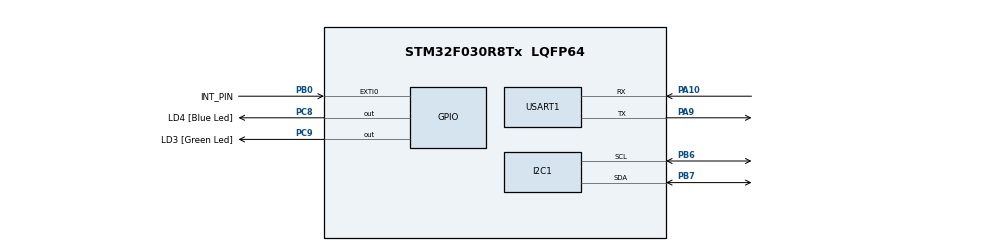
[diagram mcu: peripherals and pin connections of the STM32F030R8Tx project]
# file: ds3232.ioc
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Mcu.Family=STM32F0
PA10.Mode=Asynchronous
PC9.GPIO_Label=LD3 [Green Led]
PA14.GPIO_Label=SWCLK
PC8.Signal=GPIO_Output
PB0.GPIO_Label=INT_PIN
RCC.SYSCLKSource=RCC_SYSCLKSOURCE_PLLCLK
ProjectManager.StackSize=0x400
PC8.GPIO_Label=LD4 [Blue Led]
USART1.VirtualMode-Asynchronous=VM_ASYNC
PA13.Signal=SYS_SWDIO
PA9.Mode=Asynchronous
ProjectManager.TargetToolchain=STM32CubeIDE
RCC.HCLKFreq_Value=48000000
PA9.Signal=USART1_TX
PB6.Signal=I2C1_SCL
PB6.Mode=I2C
RCC.AHBFreq_Value=48000000
board=STM32F0308-DISCO
RCC.PLLMUL=RCC_PLL_MUL12
PB0.GPIO_ModeDefaultEXTI=GPIO_MODE_IT_FALLING
PA14.Mode=Serial_Wire
PB7.Signal=I2C1_SDA
PA13.Mode=Serial_Wire
Mcu.Name=STM32F030R8Tx
PA13.GPIO_Label=SWDIO
RCC.SYSCLKFreq_VALUE=48000000
Mcu.Package=LQFP64
PB7.Mode=I2C
PA10.Signal=USART1_RX
PA14.Signal=SYS_SWCLK
ProjectManager.HeapSize=0x200
RCC.APB1TimFreq_Value=48000000
PC9.Signal=GPIO_Output
RCC.APB1Freq_Value=48000000
PB0.Signal=GPXTI0
PB0.GPIO_PuPd=GPIO_PULLUP
NVIC.EXTI0_1_IRQn=true\:0\:0\:false\:false\:true\:true\:true

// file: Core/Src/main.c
/* USER CODE BEGIN Header */
/**
 ******************************************************************************
 * @file           : main.c
 * @brief          : Main program body
 ******************************************************************************
 * @attention
 *
 * <h2><center>&copy; Copyright (c) 2020 STMicroelectronics.
 * All rights reserved.</center></h2>
 *
 * This software component is licensed by ST under BSD 3-Clause license,
 * the "License"; You may not use this file except in compliance with the
 * License. You may obtain a copy of the License at:
 *                        opensource.org/licenses/BSD-3-Clause
 *
 ******************************************************************************
 */
/* USER CODE END Header */

#include "main.h"

/* USER CODE BEGIN Includes */
#include <stdio.h>
#include "ds3231_for_stm32_hal.h"
/* USER CODE END Includes */

I2C_HandleTypeDef hi2c1;

UART_HandleTypeDef huart1;

void SystemClock_Config(void);
static void MX_GPIO_Init(void);
static void MX_USART1_UART_Init(void);
static void MX_I2C1_Init(void);

/* USER CODE BEGIN 0 */
void printr(uint8_t reg) {
	printf("Reg 0x%02x = ", reg);
	uint8_t val;
	HAL_I2C_Master_Transmit(_ds3231_ui2c, DS3231_I2C_ADDR << 1, &reg, 1,
			DS3231_TIMEOUT);
	HAL_StatusTypeDef s = HAL_I2C_Master_Receive(_ds3231_ui2c,
			DS3231_I2C_ADDR << 1, &val, 1, DS3231_TIMEOUT);
	for (uint8_t i = 0; i < 8; i++) {
		printf("%d", (val >> (7 - i)) & 1);
	}
	printf(" With status %d", s);
	printf("\n");
}
/* USER CODE END 0 */

int main(void) {
	__disable_irq();

	/* MCU Configuration--------------------------------------------------------*/

	/* Reset of all peripherals, Initializes the Flash interface and the Systick. */
	HAL_Init();

	/* Configure the system clock */
	SystemClock_Config();

	/* Initialize all configured peripherals */
	MX_GPIO_Init();
	MX_USART1_UART_Init();
	MX_I2C1_Init();
	/* USER CODE BEGIN 2 */
	//DS3231 init function. Pass I2C handle.
	DS3231_Init(&hi2c1);
	//Disable interrupts while we set interrupt configs.
	__disable_irq();
	//Set interrupt mode to square wave mode, enable square wave interrupt at pin 3.
	DS3231_SetInterruptMode(DS3231_SQUARE_WAVE_INTERRUPT);
	//Set interrupting frequency to 1 Hz.
	DS3231_SetRateSelect(DS3231_1HZ);
	//Set time.
	DS3231_SetFullTime(23, 59, 50);
	//Set date.
	DS3231_SetFullDate(10, 11, 2, 2020);
	//Print all register values, for demonstration purpose
  	for(uint8_t i = 0x00; i < 0x13; i++)
    		printr(i);
	//Enable interrupts after finishing.
	__enable_irq();

	//Should show 5 interrupts, once every second.
	HAL_Delay(5000);

	//Set to alarm interrupt mode.
	DS3231_SetInterruptMode(DS3231_ALARM_INTERRUPT);
	DS3231_ClearAlarm1Flag();

	//Test alarm 1
	DS3231_EnableAlarm1(DS3231_ENABLED);
	DS3231_SetAlarm1Mode(DS3231_A1_MATCH_S_M_H_DATE);
	DS3231_SetAlarm1Second(3);
	DS3231_SetAlarm1Minute(0);
	DS3231_SetAlarm1Hour(0);
	DS3231_SetAlarm1Date(11);

	//Test alarm 2
	DS3231_ClearAlarm2Flag();
	DS3231_EnableAlarm2(DS3231_ENABLED);
	DS3231_SetAlarm2Mode(DS3231_A2_MATCH_M_H_DAY);
	DS3231_SetAlarm2Minute(0);
	DS3231_SetAlarm2Hour(0);
	DS3231_SetAlarm2Day(3);

	//Check if alarm behavior is correct
	__enable_irq();
	HAL_Delay(5000);
	DS3231_SetFullTime(1, 59, 59);
	DS3231_SetDate(11);
	DS3231_SetDayOfWeek(3);
	HAL_Delay(5000);
	DS3231_SetFullTime(23, 59, 59);
	DS3231_SetDate(10);
	DS3231_SetDayOfWeek(2);
	HAL_Delay(5000);
	DS3231_SetFullTime(23, 59, 59);
	DS3231_SetDate(11);
	DS3231_SetDayOfWeek(3);
	HAL_Delay(5000);

	/* USER CODE END 2 */

	/* Infinite loop */
	while (1) {

	}
}

void SystemClock_Config(void) {
	RCC_OscInitTypeDef RCC_OscInitStruct = { 0 };
	RCC_ClkInitTypeDef RCC_ClkInitStruct = { 0 };

	/** Configure the main internal regulator output voltage
	 */
	__HAL_RCC_PWR_CLK_ENABLE();
	__HAL_PWR_VOLTAGESCALING_CONFIG(PWR_REGULATOR_VOLTAGE_SCALE2);
	/** Initializes the CPU, AHB and APB busses clocks
	 */
	RCC_OscInitStruct.OscillatorType = RCC_OSCILLATORTYPE_HSE;
	RCC_OscInitStruct.HSEState = RCC_HSE_ON;
	RCC_OscInitStruct.PLL.PLLState = RCC_PLL_NONE;
	if (HAL_RCC_OscConfig(&RCC_OscInitStruct) != HAL_OK) {
		Error_Handler();
	}
	/** Initializes the CPU, AHB and APB busses clocks
	 */
	RCC_ClkInitStruct.ClockType = RCC_CLOCKTYPE_HCLK | RCC_CLOCKTYPE_SYSCLK
			| RCC_CLOCKTYPE_PCLK1 | RCC_CLOCKTYPE_PCLK2;
	RCC_ClkInitStruct.SYSCLKSource = RCC_SYSCLKSOURCE_HSE;
	RCC_ClkInitStruct.AHBCLKDivider = RCC_SYSCLK_DIV1;
	RCC_ClkInitStruct.APB1CLKDivider = RCC_HCLK_DIV1;
	RCC_ClkInitStruct.APB2CLKDivider = RCC_HCLK_DIV1;

	if (HAL_RCC_ClockConfig(&RCC_ClkInitStruct, FLASH_LATENCY_0) != HAL_OK) {
		Error_Handler();
	}
}

static void MX_I2C1_Init(void) {

	hi2c1.Instance = I2C1;
	hi2c1.Init.ClockSpeed = 100000;
	hi2c1.Init.DutyCycle = I2C_DUTYCYCLE_2;
	hi2c1.Init.OwnAddress1 = 0;
	hi2c1.Init.AddressingMode = I2C_ADDRESSINGMODE_7BIT;
	hi2c1.Init.DualAddressMode = I2C_DUALADDRESS_DISABLE;
	hi2c1.Init.OwnAddress2 = 0;
	hi2c1.Init.GeneralCallMode = I2C_GENERALCALL_DISABLE;
	hi2c1.Init.NoStretchMode = I2C_NOSTRETCH_DISABLE;
	if (HAL_I2C_Init(&hi2c1) != HAL_OK) {
		Error_Handler();
	}

}

static void MX_USART1_UART_Init(void) {

	huart1.Instance = USART1;
	huart1.Init.BaudRate = 115200;
	huart1.Init.WordLength = UART_WORDLENGTH_8B;
	huart1.Init.StopBits = UART_STOPBITS_1;
	huart1.Init.Parity = UART_PARITY_NONE;
	huart1.Init.Mode = UART_MODE_TX_RX;
	huart1.Init.HwFlowCtl = UART_HWCONTROL_NONE;
	huart1.Init.OverSampling = UART_OVERSAMPLING_16;
	if (HAL_UART_Init(&huart1) != HAL_OK) {
		Error_Handler();
	}

}

static void MX_GPIO_Init(void) {
	GPIO_InitTypeDef GPIO_InitStruct = { 0 };

	/* GPIO Ports Clock Enable */
	__HAL_RCC_GPIOC_CLK_ENABLE();
	__HAL_RCC_GPIOH_CLK_ENABLE();
	__HAL_RCC_GPIOA_CLK_ENABLE();
	__HAL_RCC_GPIOB_CLK_ENABLE();

	/*Configure GPIO pin Output Level */
	HAL_GPIO_WritePin(GPIOC, GPIO_PIN_13, GPIO_PIN_RESET);

	/*Configure GPIO pin : PC13 */
	GPIO_InitStruct.Pin = GPIO_PIN_13;
	GPIO_InitStruct.Mode = GPIO_MODE_OUTPUT_PP;
	GPIO_InitStruct.Pull = GPIO_NOPULL;
	GPIO_InitStruct.Speed = GPIO_SPEED_FREQ_LOW;
	HAL_GPIO_Init(GPIOC, &GPIO_InitStruct);

	/*Configure GPIO pin : PA0 */
	GPIO_InitStruct.Pin = GPIO_PIN_0;
	GPIO_InitStruct.Mode = GPIO_MODE_IT_FALLING;
	GPIO_InitStruct.Pull = GPIO_NOPULL;
	HAL_GPIO_Init(GPIOA, &GPIO_InitStruct);

	/* EXTI interrupt init*/
	HAL_NVIC_SetPriority(EXTI0_IRQn, 1, 0);
	HAL_NVIC_EnableIRQ(EXTI0_IRQn);

}

/* USER CODE BEGIN 4 */
int __io_putchar(int ch) {
	uint8_t temp[1] = { ch };
	HAL_UART_Transmit(&huart1, temp, 1, HAL_MAX_DELAY);
	return ch;
}
/* USER CODE END 4 */

void Error_Handler(void) {
}

/************************ (C) COPYRIGHT STMicroelectronics *****END OF FILE****/
